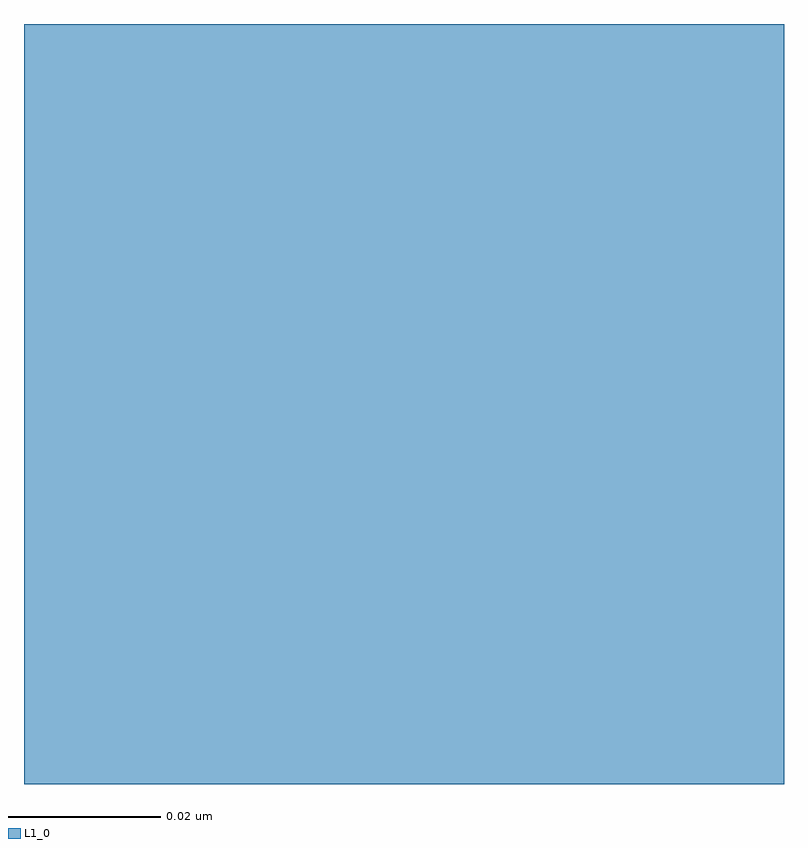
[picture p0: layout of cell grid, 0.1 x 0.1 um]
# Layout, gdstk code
import gdstk
lib = gdstk.Library(unit=1e-6, precision=1e-09)
def R(c, l, rs):  # rectangles x0, y0, x1, y1
    for r in rs: c.add(gdstk.rectangle(r[:2], r[2:], *l))
L1_0 = (1, 0)

dot = lib.new_cell('dot')
R(dot, L1_0, [(-0.001,-0.001,0.001,0.001)])

grid = lib.new_cell('grid')
R(grid, L1_0, [(0,0,0.1,0.1)])
grid.add(gdstk.Reference(dot, (0.012,0.012)))
grid.add(gdstk.Reference(dot, (0.012,0.037)))
grid.add(gdstk.Reference(dot, (0.012,0.062)))
grid.add(gdstk.Reference(dot, (0.012,0.087)))
grid.add(gdstk.Reference(dot, (0.037,0.012)))
grid.add(gdstk.Reference(dot, (0.037,0.037)))
grid.add(gdstk.Reference(dot, (0.037,0.062)))
grid.add(gdstk.Reference(dot, (0.037,0.087)))
grid.add(gdstk.Reference(dot, (0.062,0.012)))
grid.add(gdstk.Reference(dot, (0.062,0.037)))
grid.add(gdstk.Reference(dot, (0.062,0.062)))
grid.add(gdstk.Reference(dot, (0.062,0.087)))
grid.add(gdstk.Reference(dot, (0.087,0.012)))
grid.add(gdstk.Reference(dot, (0.087,0.037)))
grid.add(gdstk.Reference(dot, (0.087,0.062)))
grid.add(gdstk.Reference(dot, (0.087,0.087)))

lib.write_gds('grid.gds')
